VERSION 5.8 ;
BUSBITCHARS "[]" ;
DIVIDERCHAR "/" ;
UNITS
  DATABASE MICRONS 1000 ;
END UNITS
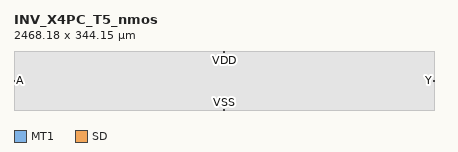
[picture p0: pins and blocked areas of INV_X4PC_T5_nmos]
MACRO INV_X4PC_T5_nmos
  CLASS BLOCK ;
  ORIGIN 0 0 ;
  FOREIGN INV_X4PC_T5_nmos 0 0 ;
  SIZE 2468.175 BY 344.15 ;
  SYMMETRY X Y ;
  PIN A
    DIRECTION INPUT ;
    USE SIGNAL ;
    PORT
      LAYER MT1 ;
        RECT 0 169.575 5 174.575 ;
    END
  END A
  PIN Y
    DIRECTION OUTPUT ;
    USE SIGNAL ;
    PORT
      LAYER MT1 ;
        RECT 2463.175 169.575 2468.175 174.575 ;
    END
  END Y
  PIN VDD
    DIRECTION INOUT ;
    USE POWER ;
    PORT
      LAYER SD ;
        RECT 1231.6 339.15 1236.6 344.15 ;
    END
  END VDD
  PIN VSS
    DIRECTION INOUT ;
    USE GROUND ;
    PORT
      LAYER SD ;
        RECT 1231.6 0 1236.6 5 ;
    END
  END VSS
  OBS
    LAYER SD ;
      RECT 0 0 2468.175 344.15 ;
  END
END INV_X4PC_T5_nmos
END LIBRARY
